# Generated by FakeRAM 2.0
VERSION 5.7 ;
BUSBITCHARS "[]" ;
PROPERTYDEFINITIONS
  MACRO width INTEGER ;
  MACRO depth INTEGER ;
  MACRO banks INTEGER ;
END PROPERTYDEFINITIONS
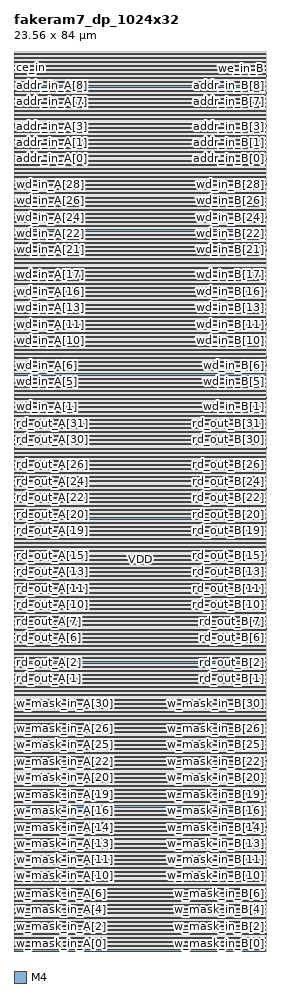
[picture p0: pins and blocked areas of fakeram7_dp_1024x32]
MACRO fakeram7_dp_1024x32
  PROPERTY width 32 ;
  PROPERTY depth 1024 ;
  PROPERTY banks 4 ;
  FOREIGN fakeram7_dp_1024x32 0 0 ;
  SYMMETRY X Y ;
  SIZE 23.560 BY 84.000 ;
  CLASS BLOCK ;
  PIN w_mask_in_A[0]
    DIRECTION INPUT ;
    USE SIGNAL ;
    SHAPE ABUTMENT ;
    PORT
      LAYER M4 ;
      RECT 0.000 0.048 0.024 0.072 ;
    END
  END w_mask_in_A[0]
  PIN w_mask_in_B[0]
    DIRECTION INPUT ;
    USE SIGNAL ;
    SHAPE ABUTMENT ;
    PORT
      LAYER M4 ;
      RECT 23.536 0.048 23.560 0.072 ;
    END
  END w_mask_in_B[0]
  PIN w_mask_in_A[1]
    DIRECTION INPUT ;
    USE SIGNAL ;
    SHAPE ABUTMENT ;
    PORT
      LAYER M4 ;
      RECT 0.000 0.816 0.024 0.840 ;
    END
  END w_mask_in_A[1]
  PIN w_mask_in_B[1]
    DIRECTION INPUT ;
    USE SIGNAL ;
    SHAPE ABUTMENT ;
    PORT
      LAYER M4 ;
      RECT 23.536 0.816 23.560 0.840 ;
    END
  END w_mask_in_B[1]
  PIN w_mask_in_A[2]
    DIRECTION INPUT ;
    USE SIGNAL ;
    SHAPE ABUTMENT ;
    PORT
      LAYER M4 ;
      RECT 0.000 1.584 0.024 1.608 ;
    END
  END w_mask_in_A[2]
  PIN w_mask_in_B[2]
    DIRECTION INPUT ;
    USE SIGNAL ;
    SHAPE ABUTMENT ;
    PORT
      LAYER M4 ;
      RECT 23.536 1.584 23.560 1.608 ;
    END
  END w_mask_in_B[2]
  PIN w_mask_in_A[3]
    DIRECTION INPUT ;
    USE SIGNAL ;
    SHAPE ABUTMENT ;
    PORT
      LAYER M4 ;
      RECT 0.000 2.352 0.024 2.376 ;
    END
  END w_mask_in_A[3]
  PIN w_mask_in_B[3]
    DIRECTION INPUT ;
    USE SIGNAL ;
    SHAPE ABUTMENT ;
    PORT
      LAYER M4 ;
      RECT 23.536 2.352 23.560 2.376 ;
    END
  END w_mask_in_B[3]
  PIN w_mask_in_A[4]
    DIRECTION INPUT ;
    USE SIGNAL ;
    SHAPE ABUTMENT ;
    PORT
      LAYER M4 ;
      RECT 0.000 3.120 0.024 3.144 ;
    END
  END w_mask_in_A[4]
  PIN w_mask_in_B[4]
    DIRECTION INPUT ;
    USE SIGNAL ;
    SHAPE ABUTMENT ;
    PORT
      LAYER M4 ;
      RECT 23.536 3.120 23.560 3.144 ;
    END
  END w_mask_in_B[4]
  PIN w_mask_in_A[5]
    DIRECTION INPUT ;
    USE SIGNAL ;
    SHAPE ABUTMENT ;
    PORT
      LAYER M4 ;
      RECT 0.000 3.888 0.024 3.912 ;
    END
  END w_mask_in_A[5]
  PIN w_mask_in_B[5]
    DIRECTION INPUT ;
    USE SIGNAL ;
    SHAPE ABUTMENT ;
    PORT
      LAYER M4 ;
      RECT 23.536 3.888 23.560 3.912 ;
    END
  END w_mask_in_B[5]
  PIN w_mask_in_A[6]
    DIRECTION INPUT ;
    USE SIGNAL ;
    SHAPE ABUTMENT ;
    PORT
      LAYER M4 ;
      RECT 0.000 4.656 0.024 4.680 ;
    END
  END w_mask_in_A[6]
  PIN w_mask_in_B[6]
    DIRECTION INPUT ;
    USE SIGNAL ;
    SHAPE ABUTMENT ;
    PORT
      LAYER M4 ;
      RECT 23.536 4.656 23.560 4.680 ;
    END
  END w_mask_in_B[6]
  PIN w_mask_in_A[7]
    DIRECTION INPUT ;
    USE SIGNAL ;
    SHAPE ABUTMENT ;
    PORT
      LAYER M4 ;
      RECT 0.000 5.424 0.024 5.448 ;
    END
  END w_mask_in_A[7]
  PIN w_mask_in_B[7]
    DIRECTION INPUT ;
    USE SIGNAL ;
    SHAPE ABUTMENT ;
    PORT
      LAYER M4 ;
      RECT 23.536 5.424 23.560 5.448 ;
    END
  END w_mask_in_B[7]
  PIN w_mask_in_A[8]
    DIRECTION INPUT ;
    USE SIGNAL ;
    SHAPE ABUTMENT ;
    PORT
      LAYER M4 ;
      RECT 0.000 6.192 0.024 6.216 ;
    END
  END w_mask_in_A[8]
  PIN w_mask_in_B[8]
    DIRECTION INPUT ;
    USE SIGNAL ;
    SHAPE ABUTMENT ;
    PORT
      LAYER M4 ;
      RECT 23.536 6.192 23.560 6.216 ;
    END
  END w_mask_in_B[8]
  PIN w_mask_in_A[9]
    DIRECTION INPUT ;
    USE SIGNAL ;
    SHAPE ABUTMENT ;
    PORT
      LAYER M4 ;
      RECT 0.000 6.960 0.024 6.984 ;
    END
  END w_mask_in_A[9]
  PIN w_mask_in_B[9]
    DIRECTION INPUT ;
    USE SIGNAL ;
    SHAPE ABUTMENT ;
    PORT
      LAYER M4 ;
      RECT 23.536 6.960 23.560 6.984 ;
    END
  END w_mask_in_B[9]
  PIN w_mask_in_A[10]
    DIRECTION INPUT ;
    USE SIGNAL ;
    SHAPE ABUTMENT ;
    PORT
      LAYER M4 ;
      RECT 0.000 7.728 0.024 7.752 ;
    END
  END w_mask_in_A[10]
  PIN w_mask_in_B[10]
    DIRECTION INPUT ;
    USE SIGNAL ;
    SHAPE ABUTMENT ;
    PORT
      LAYER M4 ;
      RECT 23.536 7.728 23.560 7.752 ;
    END
  END w_mask_in_B[10]
  PIN w_mask_in_A[11]
    DIRECTION INPUT ;
    USE SIGNAL ;
    SHAPE ABUTMENT ;
    PORT
      LAYER M4 ;
      RECT 0.000 8.496 0.024 8.520 ;
    END
  END w_mask_in_A[11]
  PIN w_mask_in_B[11]
    DIRECTION INPUT ;
    USE SIGNAL ;
    SHAPE ABUTMENT ;
    PORT
      LAYER M4 ;
      RECT 23.536 8.496 23.560 8.520 ;
    END
  END w_mask_in_B[11]
  PIN w_mask_in_A[12]
    DIRECTION INPUT ;
    USE SIGNAL ;
    SHAPE ABUTMENT ;
    PORT
      LAYER M4 ;
      RECT 0.000 9.264 0.024 9.288 ;
    END
  END w_mask_in_A[12]
  PIN w_mask_in_B[12]
    DIRECTION INPUT ;
    USE SIGNAL ;
    SHAPE ABUTMENT ;
    PORT
      LAYER M4 ;
      RECT 23.536 9.264 23.560 9.288 ;
    END
  END w_mask_in_B[12]
  PIN w_mask_in_A[13]
    DIRECTION INPUT ;
    USE SIGNAL ;
    SHAPE ABUTMENT ;
    PORT
      LAYER M4 ;
      RECT 0.000 10.032 0.024 10.056 ;
    END
  END w_mask_in_A[13]
  PIN w_mask_in_B[13]
    DIRECTION INPUT ;
    USE SIGNAL ;
    SHAPE ABUTMENT ;
    PORT
      LAYER M4 ;
      RECT 23.536 10.032 23.560 10.056 ;
    END
  END w_mask_in_B[13]
  PIN w_mask_in_A[14]
    DIRECTION INPUT ;
    USE SIGNAL ;
    SHAPE ABUTMENT ;
    PORT
      LAYER M4 ;
      RECT 0.000 10.800 0.024 10.824 ;
    END
  END w_mask_in_A[14]
  PIN w_mask_in_B[14]
    DIRECTION INPUT ;
    USE SIGNAL ;
    SHAPE ABUTMENT ;
    PORT
      LAYER M4 ;
      RECT 23.536 10.800 23.560 10.824 ;
    END
  END w_mask_in_B[14]
  PIN w_mask_in_A[15]
    DIRECTION INPUT ;
    USE SIGNAL ;
    SHAPE ABUTMENT ;
    PORT
      LAYER M4 ;
      RECT 0.000 11.568 0.024 11.592 ;
    END
  END w_mask_in_A[15]
  PIN w_mask_in_B[15]
    DIRECTION INPUT ;
    USE SIGNAL ;
    SHAPE ABUTMENT ;
    PORT
      LAYER M4 ;
      RECT 23.536 11.568 23.560 11.592 ;
    END
  END w_mask_in_B[15]
  PIN w_mask_in_A[16]
    DIRECTION INPUT ;
    USE SIGNAL ;
    SHAPE ABUTMENT ;
    PORT
      LAYER M4 ;
      RECT 0.000 12.336 0.024 12.360 ;
    END
  END w_mask_in_A[16]
  PIN w_mask_in_B[16]
    DIRECTION INPUT ;
    USE SIGNAL ;
    SHAPE ABUTMENT ;
    PORT
      LAYER M4 ;
      RECT 23.536 12.336 23.560 12.360 ;
    END
  END w_mask_in_B[16]
  PIN w_mask_in_A[17]
    DIRECTION INPUT ;
    USE SIGNAL ;
    SHAPE ABUTMENT ;
    PORT
      LAYER M4 ;
      RECT 0.000 13.104 0.024 13.128 ;
    END
  END w_mask_in_A[17]
  PIN w_mask_in_B[17]
    DIRECTION INPUT ;
    USE SIGNAL ;
    SHAPE ABUTMENT ;
    PORT
      LAYER M4 ;
      RECT 23.536 13.104 23.560 13.128 ;
    END
  END w_mask_in_B[17]
  PIN w_mask_in_A[18]
    DIRECTION INPUT ;
    USE SIGNAL ;
    SHAPE ABUTMENT ;
    PORT
      LAYER M4 ;
      RECT 0.000 13.872 0.024 13.896 ;
    END
  END w_mask_in_A[18]
  PIN w_mask_in_B[18]
    DIRECTION INPUT ;
    USE SIGNAL ;
    SHAPE ABUTMENT ;
    PORT
      LAYER M4 ;
      RECT 23.536 13.872 23.560 13.896 ;
    END
  END w_mask_in_B[18]
  PIN w_mask_in_A[19]
    DIRECTION INPUT ;
    USE SIGNAL ;
    SHAPE ABUTMENT ;
    PORT
      LAYER M4 ;
      RECT 0.000 14.640 0.024 14.664 ;
    END
  END w_mask_in_A[19]
  PIN w_mask_in_B[19]
    DIRECTION INPUT ;
    USE SIGNAL ;
    SHAPE ABUTMENT ;
    PORT
      LAYER M4 ;
      RECT 23.536 14.640 23.560 14.664 ;
    END
  END w_mask_in_B[19]
  PIN w_mask_in_A[20]
    DIRECTION INPUT ;
    USE SIGNAL ;
    SHAPE ABUTMENT ;
    PORT
      LAYER M4 ;
      RECT 0.000 15.408 0.024 15.432 ;
    END
  END w_mask_in_A[20]
  PIN w_mask_in_B[20]
    DIRECTION INPUT ;
    USE SIGNAL ;
    SHAPE ABUTMENT ;
    PORT
      LAYER M4 ;
      RECT 23.536 15.408 23.560 15.432 ;
    END
  END w_mask_in_B[20]
  PIN w_mask_in_A[21]
    DIRECTION INPUT ;
    USE SIGNAL ;
    SHAPE ABUTMENT ;
    PORT
      LAYER M4 ;
      RECT 0.000 16.176 0.024 16.200 ;
    END
  END w_mask_in_A[21]
  PIN w_mask_in_B[21]
    DIRECTION INPUT ;
    USE SIGNAL ;
    SHAPE ABUTMENT ;
    PORT
      LAYER M4 ;
      RECT 23.536 16.176 23.560 16.200 ;
    END
  END w_mask_in_B[21]
  PIN w_mask_in_A[22]
    DIRECTION INPUT ;
    USE SIGNAL ;
    SHAPE ABUTMENT ;
    PORT
      LAYER M4 ;
      RECT 0.000 16.944 0.024 16.968 ;
    END
  END w_mask_in_A[22]
  PIN w_mask_in_B[22]
    DIRECTION INPUT ;
    USE SIGNAL ;
    SHAPE ABUTMENT ;
    PORT
      LAYER M4 ;
      RECT 23.536 16.944 23.560 16.968 ;
    END
  END w_mask_in_B[22]
  PIN w_mask_in_A[23]
    DIRECTION INPUT ;
    USE SIGNAL ;
    SHAPE ABUTMENT ;
    PORT
      LAYER M4 ;
      RECT 0.000 17.712 0.024 17.736 ;
    END
  END w_mask_in_A[23]
  PIN w_mask_in_B[23]
    DIRECTION INPUT ;
    USE SIGNAL ;
    SHAPE ABUTMENT ;
    PORT
      LAYER M4 ;
      RECT 23.536 17.712 23.560 17.736 ;
    END
  END w_mask_in_B[23]
  PIN w_mask_in_A[24]
    DIRECTION INPUT ;
    USE SIGNAL ;
    SHAPE ABUTMENT ;
    PORT
      LAYER M4 ;
      RECT 0.000 18.480 0.024 18.504 ;
    END
  END w_mask_in_A[24]
  PIN w_mask_in_B[24]
    DIRECTION INPUT ;
    USE SIGNAL ;
    SHAPE ABUTMENT ;
    PORT
      LAYER M4 ;
      RECT 23.536 18.480 23.560 18.504 ;
    END
  END w_mask_in_B[24]
  PIN w_mask_in_A[25]
    DIRECTION INPUT ;
    USE SIGNAL ;
    SHAPE ABUTMENT ;
    PORT
      LAYER M4 ;
      RECT 0.000 19.248 0.024 19.272 ;
    END
  END w_mask_in_A[25]
  PIN w_mask_in_B[25]
    DIRECTION INPUT ;
    USE SIGNAL ;
    SHAPE ABUTMENT ;
    PORT
      LAYER M4 ;
      RECT 23.536 19.248 23.560 19.272 ;
    END
  END w_mask_in_B[25]
  PIN w_mask_in_A[26]
    DIRECTION INPUT ;
    USE SIGNAL ;
    SHAPE ABUTMENT ;
    PORT
      LAYER M4 ;
      RECT 0.000 20.016 0.024 20.040 ;
    END
  END w_mask_in_A[26]
  PIN w_mask_in_B[26]
    DIRECTION INPUT ;
    USE SIGNAL ;
    SHAPE ABUTMENT ;
    PORT
      LAYER M4 ;
      RECT 23.536 20.016 23.560 20.040 ;
    END
  END w_mask_in_B[26]
  PIN w_mask_in_A[27]
    DIRECTION INPUT ;
    USE SIGNAL ;
    SHAPE ABUTMENT ;
    PORT
      LAYER M4 ;
      RECT 0.000 20.784 0.024 20.808 ;
    END
  END w_mask_in_A[27]
  PIN w_mask_in_B[27]
    DIRECTION INPUT ;
    USE SIGNAL ;
    SHAPE ABUTMENT ;
    PORT
      LAYER M4 ;
      RECT 23.536 20.784 23.560 20.808 ;
    END
  END w_mask_in_B[27]
  PIN w_mask_in_A[28]
    DIRECTION INPUT ;
    USE SIGNAL ;
    SHAPE ABUTMENT ;
    PORT
      LAYER M4 ;
      RECT 0.000 21.552 0.024 21.576 ;
    END
  END w_mask_in_A[28]
  PIN w_mask_in_B[28]
    DIRECTION INPUT ;
    USE SIGNAL ;
    SHAPE ABUTMENT ;
    PORT
      LAYER M4 ;
      RECT 23.536 21.552 23.560 21.576 ;
    END
  END w_mask_in_B[28]
  PIN w_mask_in_A[29]
    DIRECTION INPUT ;
    USE SIGNAL ;
    SHAPE ABUTMENT ;
    PORT
      LAYER M4 ;
      RECT 0.000 22.320 0.024 22.344 ;
    END
  END w_mask_in_A[29]
  PIN w_mask_in_B[29]
    DIRECTION INPUT ;
    USE SIGNAL ;
    SHAPE ABUTMENT ;
    PORT
      LAYER M4 ;
      RECT 23.536 22.320 23.560 22.344 ;
    END
  END w_mask_in_B[29]
  PIN w_mask_in_A[30]
    DIRECTION INPUT ;
    USE SIGNAL ;
    SHAPE ABUTMENT ;
    PORT
      LAYER M4 ;
      RECT 0.000 23.088 0.024 23.112 ;
    END
  END w_mask_in_A[30]
  PIN w_mask_in_B[30]
    DIRECTION INPUT ;
    USE SIGNAL ;
    SHAPE ABUTMENT ;
    PORT
      LAYER M4 ;
      RECT 23.536 23.088 23.560 23.112 ;
    END
  END w_mask_in_B[30]
  PIN w_mask_in_A[31]
    DIRECTION INPUT ;
    USE SIGNAL ;
    SHAPE ABUTMENT ;
    PORT
      LAYER M4 ;
      RECT 0.000 23.856 0.024 23.880 ;
    END
  END w_mask_in_A[31]
  PIN w_mask_in_B[31]
    DIRECTION INPUT ;
    USE SIGNAL ;
    SHAPE ABUTMENT ;
    PORT
      LAYER M4 ;
      RECT 23.536 23.856 23.560 23.880 ;
    END
  END w_mask_in_B[31]
  PIN rd_out_A[0]
    DIRECTION OUTPUT ;
    USE SIGNAL ;
    SHAPE ABUTMENT ;
    PORT
      LAYER M4 ;
      RECT 0.000 24.672 0.024 24.696 ;
    END
  END rd_out_A[0]
  PIN rd_out_B[0]
    DIRECTION OUTPUT ;
    USE SIGNAL ;
    SHAPE ABUTMENT ;
    PORT
      LAYER M4 ;
      RECT 23.536 24.672 23.560 24.696 ;
    END
  END rd_out_B[0]
  PIN rd_out_A[1]
    DIRECTION OUTPUT ;
    USE SIGNAL ;
    SHAPE ABUTMENT ;
    PORT
      LAYER M4 ;
      RECT 0.000 25.440 0.024 25.464 ;
    END
  END rd_out_A[1]
  PIN rd_out_B[1]
    DIRECTION OUTPUT ;
    USE SIGNAL ;
    SHAPE ABUTMENT ;
    PORT
      LAYER M4 ;
      RECT 23.536 25.440 23.560 25.464 ;
    END
  END rd_out_B[1]
  PIN rd_out_A[2]
    DIRECTION OUTPUT ;
    USE SIGNAL ;
    SHAPE ABUTMENT ;
    PORT
      LAYER M4 ;
      RECT 0.000 26.208 0.024 26.232 ;
    END
  END rd_out_A[2]
  PIN rd_out_B[2]
    DIRECTION OUTPUT ;
    USE SIGNAL ;
    SHAPE ABUTMENT ;
    PORT
      LAYER M4 ;
      RECT 23.536 26.208 23.560 26.232 ;
    END
  END rd_out_B[2]
  PIN rd_out_A[3]
    DIRECTION OUTPUT ;
    USE SIGNAL ;
    SHAPE ABUTMENT ;
    PORT
      LAYER M4 ;
      RECT 0.000 26.976 0.024 27.000 ;
    END
  END rd_out_A[3]
  PIN rd_out_B[3]
    DIRECTION OUTPUT ;
    USE SIGNAL ;
    SHAPE ABUTMENT ;
    PORT
      LAYER M4 ;
      RECT 23.536 26.976 23.560 27.000 ;
    END
  END rd_out_B[3]
  PIN rd_out_A[4]
    DIRECTION OUTPUT ;
    USE SIGNAL ;
    SHAPE ABUTMENT ;
    PORT
      LAYER M4 ;
      RECT 0.000 27.744 0.024 27.768 ;
    END
  END rd_out_A[4]
  PIN rd_out_B[4]
    DIRECTION OUTPUT ;
    USE SIGNAL ;
    SHAPE ABUTMENT ;
    PORT
      LAYER M4 ;
      RECT 23.536 27.744 23.560 27.768 ;
    END
  END rd_out_B[4]
  PIN rd_out_A[5]
    DIRECTION OUTPUT ;
    USE SIGNAL ;
    SHAPE ABUTMENT ;
    PORT
      LAYER M4 ;
      RECT 0.000 28.512 0.024 28.536 ;
    END
  END rd_out_A[5]
  PIN rd_out_B[5]
    DIRECTION OUTPUT ;
    USE SIGNAL ;
    SHAPE ABUTMENT ;
    PORT
      LAYER M4 ;
      RECT 23.536 28.512 23.560 28.536 ;
    END
  END rd_out_B[5]
  PIN rd_out_A[6]
    DIRECTION OUTPUT ;
    USE SIGNAL ;
    SHAPE ABUTMENT ;
    PORT
      LAYER M4 ;
      RECT 0.000 29.280 0.024 29.304 ;
    END
  END rd_out_A[6]
  PIN rd_out_B[6]
    DIRECTION OUTPUT ;
    USE SIGNAL ;
    SHAPE ABUTMENT ;
    PORT
      LAYER M4 ;
      RECT 23.536 29.280 23.560 29.304 ;
    END
  END rd_out_B[6]
  PIN rd_out_A[7]
    DIRECTION OUTPUT ;
    USE SIGNAL ;
    SHAPE ABUTMENT ;
    PORT
      LAYER M4 ;
      RECT 0.000 30.048 0.024 30.072 ;
    END
  END rd_out_A[7]
  PIN rd_out_B[7]
    DIRECTION OUTPUT ;
    USE SIGNAL ;
    SHAPE ABUTMENT ;
    PORT
      LAYER M4 ;
      RECT 23.536 30.048 23.560 30.072 ;
    END
  END rd_out_B[7]
  PIN rd_out_A[8]
    DIRECTION OUTPUT ;
    USE SIGNAL ;
    SHAPE ABUTMENT ;
    PORT
      LAYER M4 ;
      RECT 0.000 30.816 0.024 30.840 ;
    END
  END rd_out_A[8]
  PIN rd_out_B[8]
    DIRECTION OUTPUT ;
    USE SIGNAL ;
    SHAPE ABUTMENT ;
    PORT
      LAYER M4 ;
      RECT 23.536 30.816 23.560 30.840 ;
    END
  END rd_out_B[8]
  PIN rd_out_A[9]
    DIRECTION OUTPUT ;
    USE SIGNAL ;
    SHAPE ABUTMENT ;
    PORT
      LAYER M4 ;
      RECT 0.000 31.584 0.024 31.608 ;
    END
  END rd_out_A[9]
  PIN rd_out_B[9]
    DIRECTION OUTPUT ;
    USE SIGNAL ;
    SHAPE ABUTMENT ;
    PORT
      LAYER M4 ;
      RECT 23.536 31.584 23.560 31.608 ;
    END
  END rd_out_B[9]
  PIN rd_out_A[10]
    DIRECTION OUTPUT ;
    USE SIGNAL ;
    SHAPE ABUTMENT ;
    PORT
      LAYER M4 ;
      RECT 0.000 32.352 0.024 32.376 ;
    END
  END rd_out_A[10]
  PIN rd_out_B[10]
    DIRECTION OUTPUT ;
    USE SIGNAL ;
    SHAPE ABUTMENT ;
    PORT
      LAYER M4 ;
      RECT 23.536 32.352 23.560 32.376 ;
    END
  END rd_out_B[10]
  PIN rd_out_A[11]
    DIRECTION OUTPUT ;
    USE SIGNAL ;
    SHAPE ABUTMENT ;
    PORT
      LAYER M4 ;
      RECT 0.000 33.120 0.024 33.144 ;
    END
  END rd_out_A[11]
  PIN rd_out_B[11]
    DIRECTION OUTPUT ;
    USE SIGNAL ;
    SHAPE ABUTMENT ;
    PORT
      LAYER M4 ;
      RECT 23.536 33.120 23.560 33.144 ;
    END
  END rd_out_B[11]
  PIN rd_out_A[12]
    DIRECTION OUTPUT ;
    USE SIGNAL ;
    SHAPE ABUTMENT ;
    PORT
      LAYER M4 ;
      RECT 0.000 33.888 0.024 33.912 ;
    END
  END rd_out_A[12]
  PIN rd_out_B[12]
    DIRECTION OUTPUT ;
    USE SIGNAL ;
    SHAPE ABUTMENT ;
    PORT
      LAYER M4 ;
      RECT 23.536 33.888 23.560 33.912 ;
    END
  END rd_out_B[12]
  PIN rd_out_A[13]
    DIRECTION OUTPUT ;
    USE SIGNAL ;
    SHAPE ABUTMENT ;
    PORT
      LAYER M4 ;
      RECT 0.000 34.656 0.024 34.680 ;
    END
  END rd_out_A[13]
  PIN rd_out_B[13]
    DIRECTION OUTPUT ;
    USE SIGNAL ;
    SHAPE ABUTMENT ;
    PORT
      LAYER M4 ;
      RECT 23.536 34.656 23.560 34.680 ;
    END
  END rd_out_B[13]
  PIN rd_out_A[14]
    DIRECTION OUTPUT ;
    USE SIGNAL ;
    SHAPE ABUTMENT ;
    PORT
      LAYER M4 ;
      RECT 0.000 35.424 0.024 35.448 ;
    END
  END rd_out_A[14]
  PIN rd_out_B[14]
    DIRECTION OUTPUT ;
    USE SIGNAL ;
    SHAPE ABUTMENT ;
    PORT
      LAYER M4 ;
      RECT 23.536 35.424 23.560 35.448 ;
    END
  END rd_out_B[14]
  PIN rd_out_A[15]
    DIRECTION OUTPUT ;
    USE SIGNAL ;
    SHAPE ABUTMENT ;
    PORT
      LAYER M4 ;
      RECT 0.000 36.192 0.024 36.216 ;
    END
  END rd_out_A[15]
  PIN rd_out_B[15]
    DIRECTION OUTPUT ;
    USE SIGNAL ;
    SHAPE ABUTMENT ;
    PORT
      LAYER M4 ;
      RECT 23.536 36.192 23.560 36.216 ;
    END
  END rd_out_B[15]
  PIN rd_out_A[16]
    DIRECTION OUTPUT ;
    USE SIGNAL ;
    SHAPE ABUTMENT ;
    PORT
      LAYER M4 ;
      RECT 0.000 36.960 0.024 36.984 ;
    END
  END rd_out_A[16]
  PIN rd_out_B[16]
    DIRECTION OUTPUT ;
    USE SIGNAL ;
    SHAPE ABUTMENT ;
    PORT
      LAYER M4 ;
      RECT 23.536 36.960 23.560 36.984 ;
    END
  END rd_out_B[16]
  PIN rd_out_A[17]
    DIRECTION OUTPUT ;
    USE SIGNAL ;
    SHAPE ABUTMENT ;
    PORT
      LAYER M4 ;
      RECT 0.000 37.728 0.024 37.752 ;
    END
  END rd_out_A[17]
  PIN rd_out_B[17]
    DIRECTION OUTPUT ;
    USE SIGNAL ;
    SHAPE ABUTMENT ;
    PORT
      LAYER M4 ;
      RECT 23.536 37.728 23.560 37.752 ;
    END
  END rd_out_B[17]
  PIN rd_out_A[18]
    DIRECTION OUTPUT ;
    USE SIGNAL ;
    SHAPE ABUTMENT ;
    PORT
      LAYER M4 ;
      RECT 0.000 38.496 0.024 38.520 ;
    END
  END rd_out_A[18]
  PIN rd_out_B[18]
    DIRECTION OUTPUT ;
    USE SIGNAL ;
    SHAPE ABUTMENT ;
    PORT
      LAYER M4 ;
      RECT 23.536 38.496 23.560 38.520 ;
    END
  END rd_out_B[18]
  PIN rd_out_A[19]
    DIRECTION OUTPUT ;
    USE SIGNAL ;
    SHAPE ABUTMENT ;
    PORT
      LAYER M4 ;
      RECT 0.000 39.264 0.024 39.288 ;
    END
  END rd_out_A[19]
  PIN rd_out_B[19]
    DIRECTION OUTPUT ;
    USE SIGNAL ;
    SHAPE ABUTMENT ;
    PORT
      LAYER M4 ;
      RECT 23.536 39.264 23.560 39.288 ;
    END
  END rd_out_B[19]
  PIN rd_out_A[20]
    DIRECTION OUTPUT ;
    USE SIGNAL ;
    SHAPE ABUTMENT ;
    PORT
      LAYER M4 ;
      RECT 0.000 40.032 0.024 40.056 ;
    END
  END rd_out_A[20]
  PIN rd_out_B[20]
    DIRECTION OUTPUT ;
    USE SIGNAL ;
    SHAPE ABUTMENT ;
    PORT
      LAYER M4 ;
      RECT 23.536 40.032 23.560 40.056 ;
    END
  END rd_out_B[20]
  PIN rd_out_A[21]
    DIRECTION OUTPUT ;
    USE SIGNAL ;
    SHAPE ABUTMENT ;
    PORT
      LAYER M4 ;
      RECT 0.000 40.800 0.024 40.824 ;
    END
  END rd_out_A[21]
  PIN rd_out_B[21]
    DIRECTION OUTPUT ;
    USE SIGNAL ;
    SHAPE ABUTMENT ;
    PORT
      LAYER M4 ;
      RECT 23.536 40.800 23.560 40.824 ;
    END
  END rd_out_B[21]
  PIN rd_out_A[22]
    DIRECTION OUTPUT ;
    USE SIGNAL ;
    SHAPE ABUTMENT ;
    PORT
      LAYER M4 ;
      RECT 0.000 41.568 0.024 41.592 ;
    END
  END rd_out_A[22]
  PIN rd_out_B[22]
    DIRECTION OUTPUT ;
    USE SIGNAL ;
    SHAPE ABUTMENT ;
    PORT
      LAYER M4 ;
      RECT 23.536 41.568 23.560 41.592 ;
    END
  END rd_out_B[22]
  PIN rd_out_A[23]
    DIRECTION OUTPUT ;
    USE SIGNAL ;
    SHAPE ABUTMENT ;
    PORT
      LAYER M4 ;
      RECT 0.000 42.336 0.024 42.360 ;
    END
  END rd_out_A[23]
  PIN rd_out_B[23]
    DIRECTION OUTPUT ;
    USE SIGNAL ;
    SHAPE ABUTMENT ;
    PORT
      LAYER M4 ;
      RECT 23.536 42.336 23.560 42.360 ;
    END
  END rd_out_B[23]
  PIN rd_out_A[24]
    DIRECTION OUTPUT ;
    USE SIGNAL ;
    SHAPE ABUTMENT ;
    PORT
      LAYER M4 ;
      RECT 0.000 43.104 0.024 43.128 ;
    END
  END rd_out_A[24]
  PIN rd_out_B[24]
    DIRECTION OUTPUT ;
    USE SIGNAL ;
    SHAPE ABUTMENT ;
    PORT
      LAYER M4 ;
      RECT 23.536 43.104 23.560 43.128 ;
    END
  END rd_out_B[24]
  PIN rd_out_A[25]
    DIRECTION OUTPUT ;
    USE SIGNAL ;
    SHAPE ABUTMENT ;
    PORT
      LAYER M4 ;
      RECT 0.000 43.872 0.024 43.896 ;
    END
  END rd_out_A[25]
  PIN rd_out_B[25]
    DIRECTION OUTPUT ;
    USE SIGNAL ;
    SHAPE ABUTMENT ;
    PORT
      LAYER M4 ;
      RECT 23.536 43.872 23.560 43.896 ;
    END
  END rd_out_B[25]
  PIN rd_out_A[26]
    DIRECTION OUTPUT ;
    USE SIGNAL ;
    SHAPE ABUTMENT ;
    PORT
      LAYER M4 ;
      RECT 0.000 44.640 0.024 44.664 ;
    END
  END rd_out_A[26]
  PIN rd_out_B[26]
    DIRECTION OUTPUT ;
    USE SIGNAL ;
    SHAPE ABUTMENT ;
    PORT
      LAYER M4 ;
      RECT 23.536 44.640 23.560 44.664 ;
    END
  END rd_out_B[26]
  PIN rd_out_A[27]
    DIRECTION OUTPUT ;
    USE SIGNAL ;
    SHAPE ABUTMENT ;
    PORT
      LAYER M4 ;
      RECT 0.000 45.408 0.024 45.432 ;
    END
  END rd_out_A[27]
  PIN rd_out_B[27]
    DIRECTION OUTPUT ;
    USE SIGNAL ;
    SHAPE ABUTMENT ;
    PORT
      LAYER M4 ;
      RECT 23.536 45.408 23.560 45.432 ;
    END
  END rd_out_B[27]
  PIN rd_out_A[28]
    DIRECTION OUTPUT ;
    USE SIGNAL ;
    SHAPE ABUTMENT ;
    PORT
      LAYER M4 ;
      RECT 0.000 46.176 0.024 46.200 ;
    END
  END rd_out_A[28]
  PIN rd_out_B[28]
    DIRECTION OUTPUT ;
    USE SIGNAL ;
    SHAPE ABUTMENT ;
    PORT
      LAYER M4 ;
      RECT 23.536 46.176 23.560 46.200 ;
    END
  END rd_out_B[28]
  PIN rd_out_A[29]
    DIRECTION OUTPUT ;
    USE SIGNAL ;
    SHAPE ABUTMENT ;
    PORT
      LAYER M4 ;
      RECT 0.000 46.944 0.024 46.968 ;
    END
  END rd_out_A[29]
  PIN rd_out_B[29]
    DIRECTION OUTPUT ;
    USE SIGNAL ;
    SHAPE ABUTMENT ;
    PORT
      LAYER M4 ;
      RECT 23.536 46.944 23.560 46.968 ;
    END
  END rd_out_B[29]
  PIN rd_out_A[30]
    DIRECTION OUTPUT ;
    USE SIGNAL ;
    SHAPE ABUTMENT ;
    PORT
      LAYER M4 ;
      RECT 0.000 47.712 0.024 47.736 ;
    END
  END rd_out_A[30]
  PIN rd_out_B[30]
    DIRECTION OUTPUT ;
    USE SIGNAL ;
    SHAPE ABUTMENT ;
    PORT
      LAYER M4 ;
      RECT 23.536 47.712 23.560 47.736 ;
    END
  END rd_out_B[30]
  PIN rd_out_A[31]
    DIRECTION OUTPUT ;
    USE SIGNAL ;
    SHAPE ABUTMENT ;
    PORT
      LAYER M4 ;
      RECT 0.000 48.480 0.024 48.504 ;
    END
  END rd_out_A[31]
  PIN rd_out_B[31]
    DIRECTION OUTPUT ;
    USE SIGNAL ;
    SHAPE ABUTMENT ;
    PORT
      LAYER M4 ;
      RECT 23.536 48.480 23.560 48.504 ;
    END
  END rd_out_B[31]
  PIN wd_in_A[0]
    DIRECTION INPUT ;
    USE SIGNAL ;
    SHAPE ABUTMENT ;
    PORT
      LAYER M4 ;
      RECT 0.000 49.296 0.024 49.320 ;
    END
  END wd_in_A[0]
  PIN wd_in_B[0]
    DIRECTION INPUT ;
    USE SIGNAL ;
    SHAPE ABUTMENT ;
    PORT
      LAYER M4 ;
      RECT 23.536 49.296 23.560 49.320 ;
    END
  END wd_in_B[0]
  PIN wd_in_A[1]
    DIRECTION INPUT ;
    USE SIGNAL ;
    SHAPE ABUTMENT ;
    PORT
      LAYER M4 ;
      RECT 0.000 50.064 0.024 50.088 ;
    END
  END wd_in_A[1]
  PIN wd_in_B[1]
    DIRECTION INPUT ;
    USE SIGNAL ;
    SHAPE ABUTMENT ;
    PORT
      LAYER M4 ;
      RECT 23.536 50.064 23.560 50.088 ;
    END
  END wd_in_B[1]
  PIN wd_in_A[2]
    DIRECTION INPUT ;
    USE SIGNAL ;
    SHAPE ABUTMENT ;
    PORT
      LAYER M4 ;
      RECT 0.000 50.832 0.024 50.856 ;
    END
  END wd_in_A[2]
  PIN wd_in_B[2]
    DIRECTION INPUT ;
    USE SIGNAL ;
    SHAPE ABUTMENT ;
    PORT
      LAYER M4 ;
      RECT 23.536 50.832 23.560 50.856 ;
    END
  END wd_in_B[2]
  PIN wd_in_A[3]
    DIRECTION INPUT ;
    USE SIGNAL ;
    SHAPE ABUTMENT ;
    PORT
      LAYER M4 ;
      RECT 0.000 51.600 0.024 51.624 ;
    END
  END wd_in_A[3]
  PIN wd_in_B[3]
    DIRECTION INPUT ;
    USE SIGNAL ;
    SHAPE ABUTMENT ;
    PORT
      LAYER M4 ;
      RECT 23.536 51.600 23.560 51.624 ;
    END
  END wd_in_B[3]
  PIN wd_in_A[4]
    DIRECTION INPUT ;
    USE SIGNAL ;
    SHAPE ABUTMENT ;
    PORT
      LAYER M4 ;
      RECT 0.000 52.368 0.024 52.392 ;
    END
  END wd_in_A[4]
  PIN wd_in_B[4]
    DIRECTION INPUT ;
    USE SIGNAL ;
    SHAPE ABUTMENT ;
    PORT
      LAYER M4 ;
      RECT 23.536 52.368 23.560 52.392 ;
    END
  END wd_in_B[4]
  PIN wd_in_A[5]
    DIRECTION INPUT ;
    USE SIGNAL ;
    SHAPE ABUTMENT ;
    PORT
      LAYER M4 ;
      RECT 0.000 53.136 0.024 53.160 ;
    END
  END wd_in_A[5]
  PIN wd_in_B[5]
    DIRECTION INPUT ;
    USE SIGNAL ;
    SHAPE ABUTMENT ;
    PORT
      LAYER M4 ;
      RECT 23.536 53.136 23.560 53.160 ;
    END
  END wd_in_B[5]
  PIN wd_in_A[6]
    DIRECTION INPUT ;
    USE SIGNAL ;
    SHAPE ABUTMENT ;
    PORT
      LAYER M4 ;
      RECT 0.000 53.904 0.024 53.928 ;
    END
  END wd_in_A[6]
  PIN wd_in_B[6]
    DIRECTION INPUT ;
    USE SIGNAL ;
    SHAPE ABUTMENT ;
    PORT
      LAYER M4 ;
      RECT 23.536 53.904 23.560 53.928 ;
    END
  END wd_in_B[6]
  PIN wd_in_A[7]
    DIRECTION INPUT ;
    USE SIGNAL ;
    SHAPE ABUTMENT ;
    PORT
      LAYER M4 ;
      RECT 0.000 54.672 0.024 54.696 ;
    END
  END wd_in_A[7]
  PIN wd_in_B[7]
    DIRECTION INPUT ;
    USE SIGNAL ;
    SHAPE ABUTMENT ;
    PORT
      LAYER M4 ;
      RECT 23.536 54.672 23.560 54.696 ;
    END
  END wd_in_B[7]
  PIN wd_in_A[8]
    DIRECTION INPUT ;
    USE SIGNAL ;
    SHAPE ABUTMENT ;
    PORT
      LAYER M4 ;
      RECT 0.000 55.440 0.024 55.464 ;
    END
  END wd_in_A[8]
  PIN wd_in_B[8]
    DIRECTION INPUT ;
    USE SIGNAL ;
    SHAPE ABUTMENT ;
    PORT
      LAYER M4 ;
      RECT 23.536 55.440 23.560 55.464 ;
    END
  END wd_in_B[8]
  PIN wd_in_A[9]
    DIRECTION INPUT ;
    USE SIGNAL ;
    SHAPE ABUTMENT ;
    PORT
      LAYER M4 ;
      RECT 0.000 56.208 0.024 56.232 ;
    END
  END wd_in_A[9]
  PIN wd_in_B[9]
    DIRECTION INPUT ;
    USE SIGNAL ;
    SHAPE ABUTMENT ;
    PORT
      LAYER M4 ;
      RECT 23.536 56.208 23.560 56.232 ;
    END
  END wd_in_B[9]
  PIN wd_in_A[10]
    DIRECTION INPUT ;
    USE SIGNAL ;
    SHAPE ABUTMENT ;
    PORT
      LAYER M4 ;
      RECT 0.000 56.976 0.024 57.000 ;
    END
  END wd_in_A[10]
  PIN wd_in_B[10]
    DIRECTION INPUT ;
    USE SIGNAL ;
    SHAPE ABUTMENT ;
    PORT
      LAYER M4 ;
      RECT 23.536 56.976 23.560 57.000 ;
    END
  END wd_in_B[10]
  PIN wd_in_A[11]
    DIRECTION INPUT ;
    USE SIGNAL ;
    SHAPE ABUTMENT ;
    PORT
      LAYER M4 ;
      RECT 0.000 57.744 0.024 57.768 ;
    END
  END wd_in_A[11]
  PIN wd_in_B[11]
    DIRECTION INPUT ;
    USE SIGNAL ;
    SHAPE ABUTMENT ;
    PORT
      LAYER M4 ;
      RECT 23.536 57.744 23.560 57.768 ;
    END
  END wd_in_B[11]
  PIN wd_in_A[12]
    DIRECTION INPUT ;
    USE SIGNAL ;
    SHAPE ABUTMENT ;
    PORT
      LAYER M4 ;
      RECT 0.000 58.512 0.024 58.536 ;
    END
  END wd_in_A[12]
  PIN wd_in_B[12]
    DIRECTION INPUT ;
    USE SIGNAL ;
    SHAPE ABUTMENT ;
    PORT
      LAYER M4 ;
      RECT 23.536 58.512 23.560 58.536 ;
    END
  END wd_in_B[12]
  PIN wd_in_A[13]
    DIRECTION INPUT ;
    USE SIGNAL ;
    SHAPE ABUTMENT ;
    PORT
      LAYER M4 ;
      RECT 0.000 59.280 0.024 59.304 ;
    END
  END wd_in_A[13]
  PIN wd_in_B[13]
    DIRECTION INPUT ;
    USE SIGNAL ;
    SHAPE ABUTMENT ;
    PORT
      LAYER M4 ;
      RECT 23.536 59.280 23.560 59.304 ;
    END
  END wd_in_B[13]
  PIN wd_in_A[14]
    DIRECTION INPUT ;
    USE SIGNAL ;
    SHAPE ABUTMENT ;
    PORT
      LAYER M4 ;
      RECT 0.000 60.048 0.024 60.072 ;
    END
  END wd_in_A[14]
  PIN wd_in_B[14]
    DIRECTION INPUT ;
    USE SIGNAL ;
    SHAPE ABUTMENT ;
    PORT
      LAYER M4 ;
      RECT 23.536 60.048 23.560 60.072 ;
    END
  END wd_in_B[14]
  PIN wd_in_A[15]
    DIRECTION INPUT ;
    USE SIGNAL ;
    SHAPE ABUTMENT ;
    PORT
      LAYER M4 ;
      RECT 0.000 60.816 0.024 60.840 ;
    END
  END wd_in_A[15]
  PIN wd_in_B[15]
    DIRECTION INPUT ;
    USE SIGNAL ;
    SHAPE ABUTMENT ;
    PORT
      LAYER M4 ;
      RECT 23.536 60.816 23.560 60.840 ;
    END
  END wd_in_B[15]
  PIN wd_in_A[16]
    DIRECTION INPUT ;
    USE SIGNAL ;
    SHAPE ABUTMENT ;
    PORT
      LAYER M4 ;
      RECT 0.000 61.584 0.024 61.608 ;
    END
  END wd_in_A[16]
  PIN wd_in_B[16]
    DIRECTION INPUT ;
    USE SIGNAL ;
    SHAPE ABUTMENT ;
    PORT
      LAYER M4 ;
      RECT 23.536 61.584 23.560 61.608 ;
    END
  END wd_in_B[16]
  PIN wd_in_A[17]
    DIRECTION INPUT ;
    USE SIGNAL ;
    SHAPE ABUTMENT ;
    PORT
      LAYER M4 ;
      RECT 0.000 62.352 0.024 62.376 ;
    END
  END wd_in_A[17]
  PIN wd_in_B[17]
    DIRECTION INPUT ;
    USE SIGNAL ;
    SHAPE ABUTMENT ;
    PORT
      LAYER M4 ;
      RECT 23.536 62.352 23.560 62.376 ;
    END
  END wd_in_B[17]
  PIN wd_in_A[18]
    DIRECTION INPUT ;
    USE SIGNAL ;
    SHAPE ABUTMENT ;
    PORT
      LAYER M4 ;
      RECT 0.000 63.120 0.024 63.144 ;
    END
  END wd_in_A[18]
  PIN wd_in_B[18]
    DIRECTION INPUT ;
    USE SIGNAL ;
    SHAPE ABUTMENT ;
    PORT
      LAYER M4 ;
      RECT 23.536 63.120 23.560 63.144 ;
    END
  END wd_in_B[18]
  PIN wd_in_A[19]
    DIRECTION INPUT ;
    USE SIGNAL ;
    SHAPE ABUTMENT ;
    PORT
      LAYER M4 ;
      RECT 0.000 63.888 0.024 63.912 ;
    END
  END wd_in_A[19]
  PIN wd_in_B[19]
    DIRECTION INPUT ;
    USE SIGNAL ;
    SHAPE ABUTMENT ;
    PORT
      LAYER M4 ;
      RECT 23.536 63.888 23.560 63.912 ;
    END
  END wd_in_B[19]
  PIN wd_in_A[20]
    DIRECTION INPUT ;
    USE SIGNAL ;
    SHAPE ABUTMENT ;
    PORT
      LAYER M4 ;
      RECT 0.000 64.656 0.024 64.680 ;
    END
  END wd_in_A[20]
  PIN wd_in_B[20]
    DIRECTION INPUT ;
    USE SIGNAL ;
    SHAPE ABUTMENT ;
    PORT
      LAYER M4 ;
      RECT 23.536 64.656 23.560 64.680 ;
    END
  END wd_in_B[20]
  PIN wd_in_A[21]
    DIRECTION INPUT ;
    USE SIGNAL ;
    SHAPE ABUTMENT ;
    PORT
      LAYER M4 ;
      RECT 0.000 65.424 0.024 65.448 ;
    END
  END wd_in_A[21]
  PIN wd_in_B[21]
    DIRECTION INPUT ;
    USE SIGNAL ;
    SHAPE ABUTMENT ;
    PORT
      LAYER M4 ;
      RECT 23.536 65.424 23.560 65.448 ;
    END
  END wd_in_B[21]
  PIN wd_in_A[22]
    DIRECTION INPUT ;
    USE SIGNAL ;
    SHAPE ABUTMENT ;
    PORT
      LAYER M4 ;
      RECT 0.000 66.192 0.024 66.216 ;
    END
  END wd_in_A[22]
  PIN wd_in_B[22]
    DIRECTION INPUT ;
    USE SIGNAL ;
    SHAPE ABUTMENT ;
    PORT
      LAYER M4 ;
      RECT 23.536 66.192 23.560 66.216 ;
    END
  END wd_in_B[22]
  PIN wd_in_A[23]
    DIRECTION INPUT ;
    USE SIGNAL ;
    SHAPE ABUTMENT ;
    PORT
      LAYER M4 ;
      RECT 0.000 66.960 0.024 66.984 ;
    END
  END wd_in_A[23]
  PIN wd_in_B[23]
    DIRECTION INPUT ;
    USE SIGNAL ;
    SHAPE ABUTMENT ;
    PORT
      LAYER M4 ;
      RECT 23.536 66.960 23.560 66.984 ;
    END
  END wd_in_B[23]
  PIN wd_in_A[24]
    DIRECTION INPUT ;
    USE SIGNAL ;
    SHAPE ABUTMENT ;
    PORT
      LAYER M4 ;
      RECT 0.000 67.728 0.024 67.752 ;
    END
  END wd_in_A[24]
  PIN wd_in_B[24]
    DIRECTION INPUT ;
    USE SIGNAL ;
    SHAPE ABUTMENT ;
    PORT
      LAYER M4 ;
      RECT 23.536 67.728 23.560 67.752 ;
    END
  END wd_in_B[24]
  PIN wd_in_A[25]
    DIRECTION INPUT ;
    USE SIGNAL ;
    SHAPE ABUTMENT ;
    PORT
      LAYER M4 ;
      RECT 0.000 68.496 0.024 68.520 ;
    END
  END wd_in_A[25]
  PIN wd_in_B[25]
    DIRECTION INPUT ;
    USE SIGNAL ;
    SHAPE ABUTMENT ;
    PORT
      LAYER M4 ;
      RECT 23.536 68.496 23.560 68.520 ;
    END
  END wd_in_B[25]
  PIN wd_in_A[26]
    DIRECTION INPUT ;
    USE SIGNAL ;
    SHAPE ABUTMENT ;
    PORT
      LAYER M4 ;
      RECT 0.000 69.264 0.024 69.288 ;
    END
  END wd_in_A[26]
  PIN wd_in_B[26]
    DIRECTION INPUT ;
    USE SIGNAL ;
    SHAPE ABUTMENT ;
    PORT
      LAYER M4 ;
      RECT 23.536 69.264 23.560 69.288 ;
    END
  END wd_in_B[26]
  PIN wd_in_A[27]
    DIRECTION INPUT ;
    USE SIGNAL ;
    SHAPE ABUTMENT ;
    PORT
      LAYER M4 ;
      RECT 0.000 70.032 0.024 70.056 ;
    END
  END wd_in_A[27]
  PIN wd_in_B[27]
    DIRECTION INPUT ;
    USE SIGNAL ;
    SHAPE ABUTMENT ;
    PORT
      LAYER M4 ;
      RECT 23.536 70.032 23.560 70.056 ;
    END
  END wd_in_B[27]
  PIN wd_in_A[28]
    DIRECTION INPUT ;
    USE SIGNAL ;
    SHAPE ABUTMENT ;
    PORT
      LAYER M4 ;
      RECT 0.000 70.800 0.024 70.824 ;
    END
  END wd_in_A[28]
  PIN wd_in_B[28]
    DIRECTION INPUT ;
    USE SIGNAL ;
    SHAPE ABUTMENT ;
    PORT
      LAYER M4 ;
      RECT 23.536 70.800 23.560 70.824 ;
    END
  END wd_in_B[28]
  PIN wd_in_A[29]
    DIRECTION INPUT ;
    USE SIGNAL ;
    SHAPE ABUTMENT ;
    PORT
      LAYER M4 ;
      RECT 0.000 71.568 0.024 71.592 ;
    END
  END wd_in_A[29]
  PIN wd_in_B[29]
    DIRECTION INPUT ;
    USE SIGNAL ;
    SHAPE ABUTMENT ;
    PORT
      LAYER M4 ;
      RECT 23.536 71.568 23.560 71.592 ;
    END
  END wd_in_B[29]
  PIN wd_in_A[30]
    DIRECTION INPUT ;
    USE SIGNAL ;
    SHAPE ABUTMENT ;
    PORT
      LAYER M4 ;
      RECT 0.000 72.336 0.024 72.360 ;
    END
  END wd_in_A[30]
  PIN wd_in_B[30]
    DIRECTION INPUT ;
    USE SIGNAL ;
    SHAPE ABUTMENT ;
    PORT
      LAYER M4 ;
      RECT 23.536 72.336 23.560 72.360 ;
    END
  END wd_in_B[30]
  PIN wd_in_A[31]
    DIRECTION INPUT ;
    USE SIGNAL ;
    SHAPE ABUTMENT ;
    PORT
      LAYER M4 ;
      RECT 0.000 73.104 0.024 73.128 ;
    END
  END wd_in_A[31]
  PIN wd_in_B[31]
    DIRECTION INPUT ;
    USE SIGNAL ;
    SHAPE ABUTMENT ;
    PORT
      LAYER M4 ;
      RECT 23.536 73.104 23.560 73.128 ;
    END
  END wd_in_B[31]
  PIN addr_in_A[0]
    DIRECTION INPUT ;
    USE SIGNAL ;
    SHAPE ABUTMENT ;
    PORT
      LAYER M4 ;
      RECT 0.000 73.920 0.024 73.944 ;
    END
  END addr_in_A[0]
  PIN addr_in_B[0]
    DIRECTION INPUT ;
    USE SIGNAL ;
    SHAPE ABUTMENT ;
    PORT
      LAYER M4 ;
      RECT 23.536 73.920 23.560 73.944 ;
    END
  END addr_in_B[0]
  PIN addr_in_A[1]
    DIRECTION INPUT ;
    USE SIGNAL ;
    SHAPE ABUTMENT ;
    PORT
      LAYER M4 ;
      RECT 0.000 74.688 0.024 74.712 ;
    END
  END addr_in_A[1]
  PIN addr_in_B[1]
    DIRECTION INPUT ;
    USE SIGNAL ;
    SHAPE ABUTMENT ;
    PORT
      LAYER M4 ;
      RECT 23.536 74.688 23.560 74.712 ;
    END
  END addr_in_B[1]
  PIN addr_in_A[2]
    DIRECTION INPUT ;
    USE SIGNAL ;
    SHAPE ABUTMENT ;
    PORT
      LAYER M4 ;
      RECT 0.000 75.456 0.024 75.480 ;
    END
  END addr_in_A[2]
  PIN addr_in_B[2]
    DIRECTION INPUT ;
    USE SIGNAL ;
    SHAPE ABUTMENT ;
    PORT
      LAYER M4 ;
      RECT 23.536 75.456 23.560 75.480 ;
    END
  END addr_in_B[2]
  PIN addr_in_A[3]
    DIRECTION INPUT ;
    USE SIGNAL ;
    SHAPE ABUTMENT ;
    PORT
      LAYER M4 ;
      RECT 0.000 76.224 0.024 76.248 ;
    END
  END addr_in_A[3]
  PIN addr_in_B[3]
    DIRECTION INPUT ;
    USE SIGNAL ;
    SHAPE ABUTMENT ;
    PORT
      LAYER M4 ;
      RECT 23.536 76.224 23.560 76.248 ;
    END
  END addr_in_B[3]
  PIN addr_in_A[4]
    DIRECTION INPUT ;
    USE SIGNAL ;
    SHAPE ABUTMENT ;
    PORT
      LAYER M4 ;
      RECT 0.000 76.992 0.024 77.016 ;
    END
  END addr_in_A[4]
  PIN addr_in_B[4]
    DIRECTION INPUT ;
    USE SIGNAL ;
    SHAPE ABUTMENT ;
    PORT
      LAYER M4 ;
      RECT 23.536 76.992 23.560 77.016 ;
    END
  END addr_in_B[4]
  PIN addr_in_A[5]
    DIRECTION INPUT ;
    USE SIGNAL ;
    SHAPE ABUTMENT ;
    PORT
      LAYER M4 ;
      RECT 0.000 77.760 0.024 77.784 ;
    END
  END addr_in_A[5]
  PIN addr_in_B[5]
    DIRECTION INPUT ;
    USE SIGNAL ;
    SHAPE ABUTMENT ;
    PORT
      LAYER M4 ;
      RECT 23.536 77.760 23.560 77.784 ;
    END
  END addr_in_B[5]
  PIN addr_in_A[6]
    DIRECTION INPUT ;
    USE SIGNAL ;
    SHAPE ABUTMENT ;
    PORT
      LAYER M4 ;
      RECT 0.000 78.528 0.024 78.552 ;
    END
  END addr_in_A[6]
  PIN addr_in_B[6]
    DIRECTION INPUT ;
    USE SIGNAL ;
    SHAPE ABUTMENT ;
    PORT
      LAYER M4 ;
      RECT 23.536 78.528 23.560 78.552 ;
    END
  END addr_in_B[6]
  PIN addr_in_A[7]
    DIRECTION INPUT ;
    USE SIGNAL ;
    SHAPE ABUTMENT ;
    PORT
      LAYER M4 ;
      RECT 0.000 79.296 0.024 79.320 ;
    END
  END addr_in_A[7]
  PIN addr_in_B[7]
    DIRECTION INPUT ;
    USE SIGNAL ;
    SHAPE ABUTMENT ;
    PORT
      LAYER M4 ;
      RECT 23.536 79.296 23.560 79.320 ;
    END
  END addr_in_B[7]
  PIN addr_in_A[8]
    DIRECTION INPUT ;
    USE SIGNAL ;
    SHAPE ABUTMENT ;
    PORT
      LAYER M4 ;
      RECT 0.000 80.064 0.024 80.088 ;
    END
  END addr_in_A[8]
  PIN addr_in_B[8]
    DIRECTION INPUT ;
    USE SIGNAL ;
    SHAPE ABUTMENT ;
    PORT
      LAYER M4 ;
      RECT 23.536 80.064 23.560 80.088 ;
    END
  END addr_in_B[8]
  PIN addr_in_A[9]
    DIRECTION INPUT ;
    USE SIGNAL ;
    SHAPE ABUTMENT ;
    PORT
      LAYER M4 ;
      RECT 0.000 80.832 0.024 80.856 ;
    END
  END addr_in_A[9]
  PIN addr_in_B[9]
    DIRECTION INPUT ;
    USE SIGNAL ;
    SHAPE ABUTMENT ;
    PORT
      LAYER M4 ;
      RECT 23.536 80.832 23.560 80.856 ;
    END
  END addr_in_B[9]
  PIN we_in_A
    DIRECTION INPUT ;
    USE SIGNAL ;
    SHAPE ABUTMENT ;
    PORT
      LAYER M4 ;
      RECT 0.000 81.648 0.024 81.672 ;
    END
  END we_in_A
  PIN we_in_B
    DIRECTION INPUT ;
    USE SIGNAL ;
    SHAPE ABUTMENT ;
    PORT
      LAYER M4 ;
      RECT 23.536 81.648 23.560 81.672 ;
    END
  END we_in_B
  PIN ce_in
    DIRECTION INPUT ;
    USE SIGNAL ;
    SHAPE ABUTMENT ;
    PORT
      LAYER M4 ;
      RECT 0.000 82.416 0.024 82.440 ;
    END
  END ce_in
  PIN clk
    DIRECTION INPUT ;
    USE SIGNAL ;
    SHAPE ABUTMENT ;
    PORT
      LAYER M4 ;
      RECT 0.000 83.184 0.024 83.208 ;
    END
  END clk
  PIN VSS
    DIRECTION INOUT ;
    USE GROUND ;
    PORT
      LAYER M4 ;
      RECT 0.048 0.000 23.512 0.096 ;
      RECT 0.048 0.768 23.512 0.864 ;
      RECT 0.048 1.536 23.512 1.632 ;
      RECT 0.048 2.304 23.512 2.400 ;
      RECT 0.048 3.072 23.512 3.168 ;
      RECT 0.048 3.840 23.512 3.936 ;
      RECT 0.048 4.608 23.512 4.704 ;
      RECT 0.048 5.376 23.512 5.472 ;
      RECT 0.048 6.144 23.512 6.240 ;
      RECT 0.048 6.912 23.512 7.008 ;
      RECT 0.048 7.680 23.512 7.776 ;
      RECT 0.048 8.448 23.512 8.544 ;
      RECT 0.048 9.216 23.512 9.312 ;
      RECT 0.048 9.984 23.512 10.080 ;
      RECT 0.048 10.752 23.512 10.848 ;
      RECT 0.048 11.520 23.512 11.616 ;
      RECT 0.048 12.288 23.512 12.384 ;
      RECT 0.048 13.056 23.512 13.152 ;
      RECT 0.048 13.824 23.512 13.920 ;
      RECT 0.048 14.592 23.512 14.688 ;
      RECT 0.048 15.360 23.512 15.456 ;
      RECT 0.048 16.128 23.512 16.224 ;
      RECT 0.048 16.896 23.512 16.992 ;
      RECT 0.048 17.664 23.512 17.760 ;
      RECT 0.048 18.432 23.512 18.528 ;
      RECT 0.048 19.200 23.512 19.296 ;
      RECT 0.048 19.968 23.512 20.064 ;
      RECT 0.048 20.736 23.512 20.832 ;
      RECT 0.048 21.504 23.512 21.600 ;
      RECT 0.048 22.272 23.512 22.368 ;
      RECT 0.048 23.040 23.512 23.136 ;
      RECT 0.048 23.808 23.512 23.904 ;
      RECT 0.048 24.576 23.512 24.672 ;
      RECT 0.048 25.344 23.512 25.440 ;
      RECT 0.048 26.112 23.512 26.208 ;
      RECT 0.048 26.880 23.512 26.976 ;
      RECT 0.048 27.648 23.512 27.744 ;
      RECT 0.048 28.416 23.512 28.512 ;
      RECT 0.048 29.184 23.512 29.280 ;
      RECT 0.048 29.952 23.512 30.048 ;
      RECT 0.048 30.720 23.512 30.816 ;
      RECT 0.048 31.488 23.512 31.584 ;
      RECT 0.048 32.256 23.512 32.352 ;
      RECT 0.048 33.024 23.512 33.120 ;
      RECT 0.048 33.792 23.512 33.888 ;
      RECT 0.048 34.560 23.512 34.656 ;
      RECT 0.048 35.328 23.512 35.424 ;
      RECT 0.048 36.096 23.512 36.192 ;
      RECT 0.048 36.864 23.512 36.960 ;
      RECT 0.048 37.632 23.512 37.728 ;
      RECT 0.048 38.400 23.512 38.496 ;
      RECT 0.048 39.168 23.512 39.264 ;
      RECT 0.048 39.936 23.512 40.032 ;
      RECT 0.048 40.704 23.512 40.800 ;
      RECT 0.048 41.472 23.512 41.568 ;
      RECT 0.048 42.240 23.512 42.336 ;
      RECT 0.048 43.008 23.512 43.104 ;
      RECT 0.048 43.776 23.512 43.872 ;
      RECT 0.048 44.544 23.512 44.640 ;
      RECT 0.048 45.312 23.512 45.408 ;
      RECT 0.048 46.080 23.512 46.176 ;
      RECT 0.048 46.848 23.512 46.944 ;
      RECT 0.048 47.616 23.512 47.712 ;
      RECT 0.048 48.384 23.512 48.480 ;
      RECT 0.048 49.152 23.512 49.248 ;
      RECT 0.048 49.920 23.512 50.016 ;
      RECT 0.048 50.688 23.512 50.784 ;
      RECT 0.048 51.456 23.512 51.552 ;
      RECT 0.048 52.224 23.512 52.320 ;
      RECT 0.048 52.992 23.512 53.088 ;
      RECT 0.048 53.760 23.512 53.856 ;
      RECT 0.048 54.528 23.512 54.624 ;
      RECT 0.048 55.296 23.512 55.392 ;
      RECT 0.048 56.064 23.512 56.160 ;
      RECT 0.048 56.832 23.512 56.928 ;
      RECT 0.048 57.600 23.512 57.696 ;
      RECT 0.048 58.368 23.512 58.464 ;
      RECT 0.048 59.136 23.512 59.232 ;
      RECT 0.048 59.904 23.512 60.000 ;
      RECT 0.048 60.672 23.512 60.768 ;
      RECT 0.048 61.440 23.512 61.536 ;
      RECT 0.048 62.208 23.512 62.304 ;
      RECT 0.048 62.976 23.512 63.072 ;
      RECT 0.048 63.744 23.512 63.840 ;
      RECT 0.048 64.512 23.512 64.608 ;
      RECT 0.048 65.280 23.512 65.376 ;
      RECT 0.048 66.048 23.512 66.144 ;
      RECT 0.048 66.816 23.512 66.912 ;
      RECT 0.048 67.584 23.512 67.680 ;
      RECT 0.048 68.352 23.512 68.448 ;
      RECT 0.048 69.120 23.512 69.216 ;
      RECT 0.048 69.888 23.512 69.984 ;
      RECT 0.048 70.656 23.512 70.752 ;
      RECT 0.048 71.424 23.512 71.520 ;
      RECT 0.048 72.192 23.512 72.288 ;
      RECT 0.048 72.960 23.512 73.056 ;
      RECT 0.048 73.728 23.512 73.824 ;
      RECT 0.048 74.496 23.512 74.592 ;
      RECT 0.048 75.264 23.512 75.360 ;
      RECT 0.048 76.032 23.512 76.128 ;
      RECT 0.048 76.800 23.512 76.896 ;
      RECT 0.048 77.568 23.512 77.664 ;
      RECT 0.048 78.336 23.512 78.432 ;
      RECT 0.048 79.104 23.512 79.200 ;
      RECT 0.048 79.872 23.512 79.968 ;
      RECT 0.048 80.640 23.512 80.736 ;
      RECT 0.048 81.408 23.512 81.504 ;
      RECT 0.048 82.176 23.512 82.272 ;
      RECT 0.048 82.944 23.512 83.040 ;
      RECT 0.048 83.712 23.512 83.808 ;
    END
  END VSS
  PIN VDD
    DIRECTION INOUT ;
    USE POWER ;
    PORT
      LAYER M4 ;
      RECT 0.048 0.384 23.512 0.480 ;
      RECT 0.048 1.152 23.512 1.248 ;
      RECT 0.048 1.920 23.512 2.016 ;
      RECT 0.048 2.688 23.512 2.784 ;
      RECT 0.048 3.456 23.512 3.552 ;
      RECT 0.048 4.224 23.512 4.320 ;
      RECT 0.048 4.992 23.512 5.088 ;
      RECT 0.048 5.760 23.512 5.856 ;
      RECT 0.048 6.528 23.512 6.624 ;
      RECT 0.048 7.296 23.512 7.392 ;
      RECT 0.048 8.064 23.512 8.160 ;
      RECT 0.048 8.832 23.512 8.928 ;
      RECT 0.048 9.600 23.512 9.696 ;
      RECT 0.048 10.368 23.512 10.464 ;
      RECT 0.048 11.136 23.512 11.232 ;
      RECT 0.048 11.904 23.512 12.000 ;
      RECT 0.048 12.672 23.512 12.768 ;
      RECT 0.048 13.440 23.512 13.536 ;
      RECT 0.048 14.208 23.512 14.304 ;
      RECT 0.048 14.976 23.512 15.072 ;
      RECT 0.048 15.744 23.512 15.840 ;
      RECT 0.048 16.512 23.512 16.608 ;
      RECT 0.048 17.280 23.512 17.376 ;
      RECT 0.048 18.048 23.512 18.144 ;
      RECT 0.048 18.816 23.512 18.912 ;
      RECT 0.048 19.584 23.512 19.680 ;
      RECT 0.048 20.352 23.512 20.448 ;
      RECT 0.048 21.120 23.512 21.216 ;
      RECT 0.048 21.888 23.512 21.984 ;
      RECT 0.048 22.656 23.512 22.752 ;
      RECT 0.048 23.424 23.512 23.520 ;
      RECT 0.048 24.192 23.512 24.288 ;
      RECT 0.048 24.960 23.512 25.056 ;
      RECT 0.048 25.728 23.512 25.824 ;
      RECT 0.048 26.496 23.512 26.592 ;
      RECT 0.048 27.264 23.512 27.360 ;
      RECT 0.048 28.032 23.512 28.128 ;
      RECT 0.048 28.800 23.512 28.896 ;
      RECT 0.048 29.568 23.512 29.664 ;
      RECT 0.048 30.336 23.512 30.432 ;
      RECT 0.048 31.104 23.512 31.200 ;
      RECT 0.048 31.872 23.512 31.968 ;
      RECT 0.048 32.640 23.512 32.736 ;
      RECT 0.048 33.408 23.512 33.504 ;
      RECT 0.048 34.176 23.512 34.272 ;
      RECT 0.048 34.944 23.512 35.040 ;
      RECT 0.048 35.712 23.512 35.808 ;
      RECT 0.048 36.480 23.512 36.576 ;
      RECT 0.048 37.248 23.512 37.344 ;
      RECT 0.048 38.016 23.512 38.112 ;
      RECT 0.048 38.784 23.512 38.880 ;
      RECT 0.048 39.552 23.512 39.648 ;
      RECT 0.048 40.320 23.512 40.416 ;
      RECT 0.048 41.088 23.512 41.184 ;
      RECT 0.048 41.856 23.512 41.952 ;
      RECT 0.048 42.624 23.512 42.720 ;
      RECT 0.048 43.392 23.512 43.488 ;
      RECT 0.048 44.160 23.512 44.256 ;
      RECT 0.048 44.928 23.512 45.024 ;
      RECT 0.048 45.696 23.512 45.792 ;
      RECT 0.048 46.464 23.512 46.560 ;
      RECT 0.048 47.232 23.512 47.328 ;
      RECT 0.048 48.000 23.512 48.096 ;
      RECT 0.048 48.768 23.512 48.864 ;
      RECT 0.048 49.536 23.512 49.632 ;
      RECT 0.048 50.304 23.512 50.400 ;
      RECT 0.048 51.072 23.512 51.168 ;
      RECT 0.048 51.840 23.512 51.936 ;
      RECT 0.048 52.608 23.512 52.704 ;
      RECT 0.048 53.376 23.512 53.472 ;
      RECT 0.048 54.144 23.512 54.240 ;
      RECT 0.048 54.912 23.512 55.008 ;
      RECT 0.048 55.680 23.512 55.776 ;
      RECT 0.048 56.448 23.512 56.544 ;
      RECT 0.048 57.216 23.512 57.312 ;
      RECT 0.048 57.984 23.512 58.080 ;
      RECT 0.048 58.752 23.512 58.848 ;
      RECT 0.048 59.520 23.512 59.616 ;
      RECT 0.048 60.288 23.512 60.384 ;
      RECT 0.048 61.056 23.512 61.152 ;
      RECT 0.048 61.824 23.512 61.920 ;
      RECT 0.048 62.592 23.512 62.688 ;
      RECT 0.048 63.360 23.512 63.456 ;
      RECT 0.048 64.128 23.512 64.224 ;
      RECT 0.048 64.896 23.512 64.992 ;
      RECT 0.048 65.664 23.512 65.760 ;
      RECT 0.048 66.432 23.512 66.528 ;
      RECT 0.048 67.200 23.512 67.296 ;
      RECT 0.048 67.968 23.512 68.064 ;
      RECT 0.048 68.736 23.512 68.832 ;
      RECT 0.048 69.504 23.512 69.600 ;
      RECT 0.048 70.272 23.512 70.368 ;
      RECT 0.048 71.040 23.512 71.136 ;
      RECT 0.048 71.808 23.512 71.904 ;
      RECT 0.048 72.576 23.512 72.672 ;
      RECT 0.048 73.344 23.512 73.440 ;
      RECT 0.048 74.112 23.512 74.208 ;
      RECT 0.048 74.880 23.512 74.976 ;
      RECT 0.048 75.648 23.512 75.744 ;
      RECT 0.048 76.416 23.512 76.512 ;
      RECT 0.048 77.184 23.512 77.280 ;
      RECT 0.048 77.952 23.512 78.048 ;
      RECT 0.048 78.720 23.512 78.816 ;
      RECT 0.048 79.488 23.512 79.584 ;
      RECT 0.048 80.256 23.512 80.352 ;
      RECT 0.048 81.024 23.512 81.120 ;
      RECT 0.048 81.792 23.512 81.888 ;
      RECT 0.048 82.560 23.512 82.656 ;
      RECT 0.048 83.328 23.512 83.424 ;
    END
  END VDD
  OBS
    LAYER M1 ;
    RECT 0 0 23.560 84.000 ;
    LAYER M2 ;
    RECT 0 0 23.560 84.000 ;
    LAYER M3 ;
    RECT 0 0 23.560 84.000 ;
    LAYER M4 ;
    RECT 0 0 23.560 84.000 ;
  END
END fakeram7_dp_1024x32

END LIBRARY
